# Generated by FakeRAM 2.0
VERSION 5.7 ;
BUSBITCHARS "[]" ;
PROPERTYDEFINITIONS
  MACRO width INTEGER ;
  MACRO depth INTEGER ;
  MACRO banks INTEGER ;
END PROPERTYDEFINITIONS
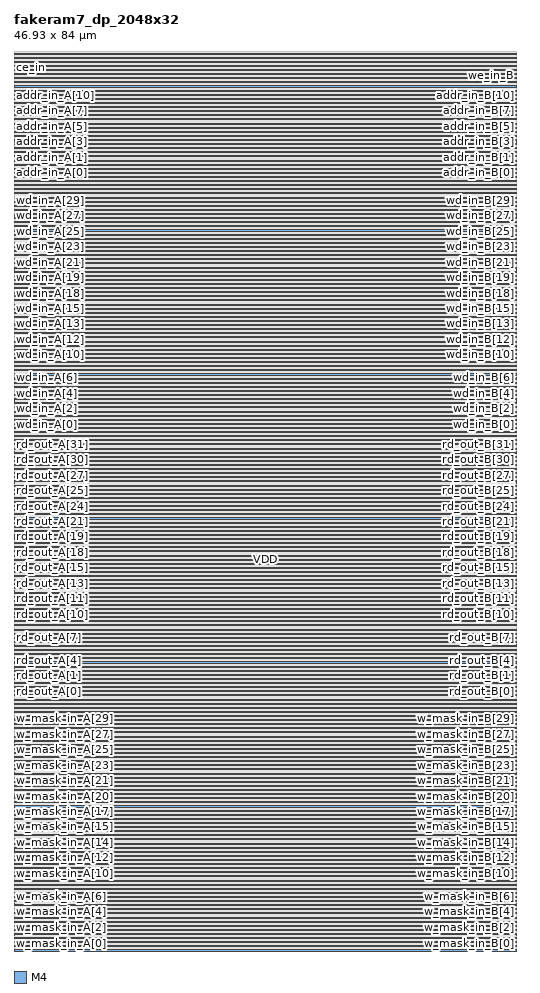
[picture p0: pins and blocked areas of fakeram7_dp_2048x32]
MACRO fakeram7_dp_2048x32
  PROPERTY width 32 ;
  PROPERTY depth 2048 ;
  PROPERTY banks 8 ;
  FOREIGN fakeram7_dp_2048x32 0 0 ;
  SYMMETRY X Y ;
  SIZE 46.930 BY 84.000 ;
  CLASS BLOCK ;
  PIN w_mask_in_A[0]
    DIRECTION INPUT ;
    USE SIGNAL ;
    SHAPE ABUTMENT ;
    PORT
      LAYER M4 ;
      RECT 0.000 0.048 0.024 0.072 ;
    END
  END w_mask_in_A[0]
  PIN w_mask_in_B[0]
    DIRECTION INPUT ;
    USE SIGNAL ;
    SHAPE ABUTMENT ;
    PORT
      LAYER M4 ;
      RECT 46.906 0.048 46.930 0.072 ;
    END
  END w_mask_in_B[0]
  PIN w_mask_in_A[1]
    DIRECTION INPUT ;
    USE SIGNAL ;
    SHAPE ABUTMENT ;
    PORT
      LAYER M4 ;
      RECT 0.000 0.768 0.024 0.792 ;
    END
  END w_mask_in_A[1]
  PIN w_mask_in_B[1]
    DIRECTION INPUT ;
    USE SIGNAL ;
    SHAPE ABUTMENT ;
    PORT
      LAYER M4 ;
      RECT 46.906 0.768 46.930 0.792 ;
    END
  END w_mask_in_B[1]
  PIN w_mask_in_A[2]
    DIRECTION INPUT ;
    USE SIGNAL ;
    SHAPE ABUTMENT ;
    PORT
      LAYER M4 ;
      RECT 0.000 1.488 0.024 1.512 ;
    END
  END w_mask_in_A[2]
  PIN w_mask_in_B[2]
    DIRECTION INPUT ;
    USE SIGNAL ;
    SHAPE ABUTMENT ;
    PORT
      LAYER M4 ;
      RECT 46.906 1.488 46.930 1.512 ;
    END
  END w_mask_in_B[2]
  PIN w_mask_in_A[3]
    DIRECTION INPUT ;
    USE SIGNAL ;
    SHAPE ABUTMENT ;
    PORT
      LAYER M4 ;
      RECT 0.000 2.208 0.024 2.232 ;
    END
  END w_mask_in_A[3]
  PIN w_mask_in_B[3]
    DIRECTION INPUT ;
    USE SIGNAL ;
    SHAPE ABUTMENT ;
    PORT
      LAYER M4 ;
      RECT 46.906 2.208 46.930 2.232 ;
    END
  END w_mask_in_B[3]
  PIN w_mask_in_A[4]
    DIRECTION INPUT ;
    USE SIGNAL ;
    SHAPE ABUTMENT ;
    PORT
      LAYER M4 ;
      RECT 0.000 2.928 0.024 2.952 ;
    END
  END w_mask_in_A[4]
  PIN w_mask_in_B[4]
    DIRECTION INPUT ;
    USE SIGNAL ;
    SHAPE ABUTMENT ;
    PORT
      LAYER M4 ;
      RECT 46.906 2.928 46.930 2.952 ;
    END
  END w_mask_in_B[4]
  PIN w_mask_in_A[5]
    DIRECTION INPUT ;
    USE SIGNAL ;
    SHAPE ABUTMENT ;
    PORT
      LAYER M4 ;
      RECT 0.000 3.648 0.024 3.672 ;
    END
  END w_mask_in_A[5]
  PIN w_mask_in_B[5]
    DIRECTION INPUT ;
    USE SIGNAL ;
    SHAPE ABUTMENT ;
    PORT
      LAYER M4 ;
      RECT 46.906 3.648 46.930 3.672 ;
    END
  END w_mask_in_B[5]
  PIN w_mask_in_A[6]
    DIRECTION INPUT ;
    USE SIGNAL ;
    SHAPE ABUTMENT ;
    PORT
      LAYER M4 ;
      RECT 0.000 4.368 0.024 4.392 ;
    END
  END w_mask_in_A[6]
  PIN w_mask_in_B[6]
    DIRECTION INPUT ;
    USE SIGNAL ;
    SHAPE ABUTMENT ;
    PORT
      LAYER M4 ;
      RECT 46.906 4.368 46.930 4.392 ;
    END
  END w_mask_in_B[6]
  PIN w_mask_in_A[7]
    DIRECTION INPUT ;
    USE SIGNAL ;
    SHAPE ABUTMENT ;
    PORT
      LAYER M4 ;
      RECT 0.000 5.088 0.024 5.112 ;
    END
  END w_mask_in_A[7]
  PIN w_mask_in_B[7]
    DIRECTION INPUT ;
    USE SIGNAL ;
    SHAPE ABUTMENT ;
    PORT
      LAYER M4 ;
      RECT 46.906 5.088 46.930 5.112 ;
    END
  END w_mask_in_B[7]
  PIN w_mask_in_A[8]
    DIRECTION INPUT ;
    USE SIGNAL ;
    SHAPE ABUTMENT ;
    PORT
      LAYER M4 ;
      RECT 0.000 5.808 0.024 5.832 ;
    END
  END w_mask_in_A[8]
  PIN w_mask_in_B[8]
    DIRECTION INPUT ;
    USE SIGNAL ;
    SHAPE ABUTMENT ;
    PORT
      LAYER M4 ;
      RECT 46.906 5.808 46.930 5.832 ;
    END
  END w_mask_in_B[8]
  PIN w_mask_in_A[9]
    DIRECTION INPUT ;
    USE SIGNAL ;
    SHAPE ABUTMENT ;
    PORT
      LAYER M4 ;
      RECT 0.000 6.528 0.024 6.552 ;
    END
  END w_mask_in_A[9]
  PIN w_mask_in_B[9]
    DIRECTION INPUT ;
    USE SIGNAL ;
    SHAPE ABUTMENT ;
    PORT
      LAYER M4 ;
      RECT 46.906 6.528 46.930 6.552 ;
    END
  END w_mask_in_B[9]
  PIN w_mask_in_A[10]
    DIRECTION INPUT ;
    USE SIGNAL ;
    SHAPE ABUTMENT ;
    PORT
      LAYER M4 ;
      RECT 0.000 7.248 0.024 7.272 ;
    END
  END w_mask_in_A[10]
  PIN w_mask_in_B[10]
    DIRECTION INPUT ;
    USE SIGNAL ;
    SHAPE ABUTMENT ;
    PORT
      LAYER M4 ;
      RECT 46.906 7.248 46.930 7.272 ;
    END
  END w_mask_in_B[10]
  PIN w_mask_in_A[11]
    DIRECTION INPUT ;
    USE SIGNAL ;
    SHAPE ABUTMENT ;
    PORT
      LAYER M4 ;
      RECT 0.000 7.968 0.024 7.992 ;
    END
  END w_mask_in_A[11]
  PIN w_mask_in_B[11]
    DIRECTION INPUT ;
    USE SIGNAL ;
    SHAPE ABUTMENT ;
    PORT
      LAYER M4 ;
      RECT 46.906 7.968 46.930 7.992 ;
    END
  END w_mask_in_B[11]
  PIN w_mask_in_A[12]
    DIRECTION INPUT ;
    USE SIGNAL ;
    SHAPE ABUTMENT ;
    PORT
      LAYER M4 ;
      RECT 0.000 8.688 0.024 8.712 ;
    END
  END w_mask_in_A[12]
  PIN w_mask_in_B[12]
    DIRECTION INPUT ;
    USE SIGNAL ;
    SHAPE ABUTMENT ;
    PORT
      LAYER M4 ;
      RECT 46.906 8.688 46.930 8.712 ;
    END
  END w_mask_in_B[12]
  PIN w_mask_in_A[13]
    DIRECTION INPUT ;
    USE SIGNAL ;
    SHAPE ABUTMENT ;
    PORT
      LAYER M4 ;
      RECT 0.000 9.408 0.024 9.432 ;
    END
  END w_mask_in_A[13]
  PIN w_mask_in_B[13]
    DIRECTION INPUT ;
    USE SIGNAL ;
    SHAPE ABUTMENT ;
    PORT
      LAYER M4 ;
      RECT 46.906 9.408 46.930 9.432 ;
    END
  END w_mask_in_B[13]
  PIN w_mask_in_A[14]
    DIRECTION INPUT ;
    USE SIGNAL ;
    SHAPE ABUTMENT ;
    PORT
      LAYER M4 ;
      RECT 0.000 10.128 0.024 10.152 ;
    END
  END w_mask_in_A[14]
  PIN w_mask_in_B[14]
    DIRECTION INPUT ;
    USE SIGNAL ;
    SHAPE ABUTMENT ;
    PORT
      LAYER M4 ;
      RECT 46.906 10.128 46.930 10.152 ;
    END
  END w_mask_in_B[14]
  PIN w_mask_in_A[15]
    DIRECTION INPUT ;
    USE SIGNAL ;
    SHAPE ABUTMENT ;
    PORT
      LAYER M4 ;
      RECT 0.000 10.848 0.024 10.872 ;
    END
  END w_mask_in_A[15]
  PIN w_mask_in_B[15]
    DIRECTION INPUT ;
    USE SIGNAL ;
    SHAPE ABUTMENT ;
    PORT
      LAYER M4 ;
      RECT 46.906 10.848 46.930 10.872 ;
    END
  END w_mask_in_B[15]
  PIN w_mask_in_A[16]
    DIRECTION INPUT ;
    USE SIGNAL ;
    SHAPE ABUTMENT ;
    PORT
      LAYER M4 ;
      RECT 0.000 11.568 0.024 11.592 ;
    END
  END w_mask_in_A[16]
  PIN w_mask_in_B[16]
    DIRECTION INPUT ;
    USE SIGNAL ;
    SHAPE ABUTMENT ;
    PORT
      LAYER M4 ;
      RECT 46.906 11.568 46.930 11.592 ;
    END
  END w_mask_in_B[16]
  PIN w_mask_in_A[17]
    DIRECTION INPUT ;
    USE SIGNAL ;
    SHAPE ABUTMENT ;
    PORT
      LAYER M4 ;
      RECT 0.000 12.288 0.024 12.312 ;
    END
  END w_mask_in_A[17]
  PIN w_mask_in_B[17]
    DIRECTION INPUT ;
    USE SIGNAL ;
    SHAPE ABUTMENT ;
    PORT
      LAYER M4 ;
      RECT 46.906 12.288 46.930 12.312 ;
    END
  END w_mask_in_B[17]
  PIN w_mask_in_A[18]
    DIRECTION INPUT ;
    USE SIGNAL ;
    SHAPE ABUTMENT ;
    PORT
      LAYER M4 ;
      RECT 0.000 13.008 0.024 13.032 ;
    END
  END w_mask_in_A[18]
  PIN w_mask_in_B[18]
    DIRECTION INPUT ;
    USE SIGNAL ;
    SHAPE ABUTMENT ;
    PORT
      LAYER M4 ;
      RECT 46.906 13.008 46.930 13.032 ;
    END
  END w_mask_in_B[18]
  PIN w_mask_in_A[19]
    DIRECTION INPUT ;
    USE SIGNAL ;
    SHAPE ABUTMENT ;
    PORT
      LAYER M4 ;
      RECT 0.000 13.728 0.024 13.752 ;
    END
  END w_mask_in_A[19]
  PIN w_mask_in_B[19]
    DIRECTION INPUT ;
    USE SIGNAL ;
    SHAPE ABUTMENT ;
    PORT
      LAYER M4 ;
      RECT 46.906 13.728 46.930 13.752 ;
    END
  END w_mask_in_B[19]
  PIN w_mask_in_A[20]
    DIRECTION INPUT ;
    USE SIGNAL ;
    SHAPE ABUTMENT ;
    PORT
      LAYER M4 ;
      RECT 0.000 14.448 0.024 14.472 ;
    END
  END w_mask_in_A[20]
  PIN w_mask_in_B[20]
    DIRECTION INPUT ;
    USE SIGNAL ;
    SHAPE ABUTMENT ;
    PORT
      LAYER M4 ;
      RECT 46.906 14.448 46.930 14.472 ;
    END
  END w_mask_in_B[20]
  PIN w_mask_in_A[21]
    DIRECTION INPUT ;
    USE SIGNAL ;
    SHAPE ABUTMENT ;
    PORT
      LAYER M4 ;
      RECT 0.000 15.168 0.024 15.192 ;
    END
  END w_mask_in_A[21]
  PIN w_mask_in_B[21]
    DIRECTION INPUT ;
    USE SIGNAL ;
    SHAPE ABUTMENT ;
    PORT
      LAYER M4 ;
      RECT 46.906 15.168 46.930 15.192 ;
    END
  END w_mask_in_B[21]
  PIN w_mask_in_A[22]
    DIRECTION INPUT ;
    USE SIGNAL ;
    SHAPE ABUTMENT ;
    PORT
      LAYER M4 ;
      RECT 0.000 15.888 0.024 15.912 ;
    END
  END w_mask_in_A[22]
  PIN w_mask_in_B[22]
    DIRECTION INPUT ;
    USE SIGNAL ;
    SHAPE ABUTMENT ;
    PORT
      LAYER M4 ;
      RECT 46.906 15.888 46.930 15.912 ;
    END
  END w_mask_in_B[22]
  PIN w_mask_in_A[23]
    DIRECTION INPUT ;
    USE SIGNAL ;
    SHAPE ABUTMENT ;
    PORT
      LAYER M4 ;
      RECT 0.000 16.608 0.024 16.632 ;
    END
  END w_mask_in_A[23]
  PIN w_mask_in_B[23]
    DIRECTION INPUT ;
    USE SIGNAL ;
    SHAPE ABUTMENT ;
    PORT
      LAYER M4 ;
      RECT 46.906 16.608 46.930 16.632 ;
    END
  END w_mask_in_B[23]
  PIN w_mask_in_A[24]
    DIRECTION INPUT ;
    USE SIGNAL ;
    SHAPE ABUTMENT ;
    PORT
      LAYER M4 ;
      RECT 0.000 17.328 0.024 17.352 ;
    END
  END w_mask_in_A[24]
  PIN w_mask_in_B[24]
    DIRECTION INPUT ;
    USE SIGNAL ;
    SHAPE ABUTMENT ;
    PORT
      LAYER M4 ;
      RECT 46.906 17.328 46.930 17.352 ;
    END
  END w_mask_in_B[24]
  PIN w_mask_in_A[25]
    DIRECTION INPUT ;
    USE SIGNAL ;
    SHAPE ABUTMENT ;
    PORT
      LAYER M4 ;
      RECT 0.000 18.048 0.024 18.072 ;
    END
  END w_mask_in_A[25]
  PIN w_mask_in_B[25]
    DIRECTION INPUT ;
    USE SIGNAL ;
    SHAPE ABUTMENT ;
    PORT
      LAYER M4 ;
      RECT 46.906 18.048 46.930 18.072 ;
    END
  END w_mask_in_B[25]
  PIN w_mask_in_A[26]
    DIRECTION INPUT ;
    USE SIGNAL ;
    SHAPE ABUTMENT ;
    PORT
      LAYER M4 ;
      RECT 0.000 18.768 0.024 18.792 ;
    END
  END w_mask_in_A[26]
  PIN w_mask_in_B[26]
    DIRECTION INPUT ;
    USE SIGNAL ;
    SHAPE ABUTMENT ;
    PORT
      LAYER M4 ;
      RECT 46.906 18.768 46.930 18.792 ;
    END
  END w_mask_in_B[26]
  PIN w_mask_in_A[27]
    DIRECTION INPUT ;
    USE SIGNAL ;
    SHAPE ABUTMENT ;
    PORT
      LAYER M4 ;
      RECT 0.000 19.488 0.024 19.512 ;
    END
  END w_mask_in_A[27]
  PIN w_mask_in_B[27]
    DIRECTION INPUT ;
    USE SIGNAL ;
    SHAPE ABUTMENT ;
    PORT
      LAYER M4 ;
      RECT 46.906 19.488 46.930 19.512 ;
    END
  END w_mask_in_B[27]
  PIN w_mask_in_A[28]
    DIRECTION INPUT ;
    USE SIGNAL ;
    SHAPE ABUTMENT ;
    PORT
      LAYER M4 ;
      RECT 0.000 20.208 0.024 20.232 ;
    END
  END w_mask_in_A[28]
  PIN w_mask_in_B[28]
    DIRECTION INPUT ;
    USE SIGNAL ;
    SHAPE ABUTMENT ;
    PORT
      LAYER M4 ;
      RECT 46.906 20.208 46.930 20.232 ;
    END
  END w_mask_in_B[28]
  PIN w_mask_in_A[29]
    DIRECTION INPUT ;
    USE SIGNAL ;
    SHAPE ABUTMENT ;
    PORT
      LAYER M4 ;
      RECT 0.000 20.928 0.024 20.952 ;
    END
  END w_mask_in_A[29]
  PIN w_mask_in_B[29]
    DIRECTION INPUT ;
    USE SIGNAL ;
    SHAPE ABUTMENT ;
    PORT
      LAYER M4 ;
      RECT 46.906 20.928 46.930 20.952 ;
    END
  END w_mask_in_B[29]
  PIN w_mask_in_A[30]
    DIRECTION INPUT ;
    USE SIGNAL ;
    SHAPE ABUTMENT ;
    PORT
      LAYER M4 ;
      RECT 0.000 21.648 0.024 21.672 ;
    END
  END w_mask_in_A[30]
  PIN w_mask_in_B[30]
    DIRECTION INPUT ;
    USE SIGNAL ;
    SHAPE ABUTMENT ;
    PORT
      LAYER M4 ;
      RECT 46.906 21.648 46.930 21.672 ;
    END
  END w_mask_in_B[30]
  PIN w_mask_in_A[31]
    DIRECTION INPUT ;
    USE SIGNAL ;
    SHAPE ABUTMENT ;
    PORT
      LAYER M4 ;
      RECT 0.000 22.368 0.024 22.392 ;
    END
  END w_mask_in_A[31]
  PIN w_mask_in_B[31]
    DIRECTION INPUT ;
    USE SIGNAL ;
    SHAPE ABUTMENT ;
    PORT
      LAYER M4 ;
      RECT 46.906 22.368 46.930 22.392 ;
    END
  END w_mask_in_B[31]
  PIN rd_out_A[0]
    DIRECTION OUTPUT ;
    USE SIGNAL ;
    SHAPE ABUTMENT ;
    PORT
      LAYER M4 ;
      RECT 0.000 24.240 0.024 24.264 ;
    END
  END rd_out_A[0]
  PIN rd_out_B[0]
    DIRECTION OUTPUT ;
    USE SIGNAL ;
    SHAPE ABUTMENT ;
    PORT
      LAYER M4 ;
      RECT 46.906 24.240 46.930 24.264 ;
    END
  END rd_out_B[0]
  PIN rd_out_A[1]
    DIRECTION OUTPUT ;
    USE SIGNAL ;
    SHAPE ABUTMENT ;
    PORT
      LAYER M4 ;
      RECT 0.000 24.960 0.024 24.984 ;
    END
  END rd_out_A[1]
  PIN rd_out_B[1]
    DIRECTION OUTPUT ;
    USE SIGNAL ;
    SHAPE ABUTMENT ;
    PORT
      LAYER M4 ;
      RECT 46.906 24.960 46.930 24.984 ;
    END
  END rd_out_B[1]
  PIN rd_out_A[2]
    DIRECTION OUTPUT ;
    USE SIGNAL ;
    SHAPE ABUTMENT ;
    PORT
      LAYER M4 ;
      RECT 0.000 25.680 0.024 25.704 ;
    END
  END rd_out_A[2]
  PIN rd_out_B[2]
    DIRECTION OUTPUT ;
    USE SIGNAL ;
    SHAPE ABUTMENT ;
    PORT
      LAYER M4 ;
      RECT 46.906 25.680 46.930 25.704 ;
    END
  END rd_out_B[2]
  PIN rd_out_A[3]
    DIRECTION OUTPUT ;
    USE SIGNAL ;
    SHAPE ABUTMENT ;
    PORT
      LAYER M4 ;
      RECT 0.000 26.400 0.024 26.424 ;
    END
  END rd_out_A[3]
  PIN rd_out_B[3]
    DIRECTION OUTPUT ;
    USE SIGNAL ;
    SHAPE ABUTMENT ;
    PORT
      LAYER M4 ;
      RECT 46.906 26.400 46.930 26.424 ;
    END
  END rd_out_B[3]
  PIN rd_out_A[4]
    DIRECTION OUTPUT ;
    USE SIGNAL ;
    SHAPE ABUTMENT ;
    PORT
      LAYER M4 ;
      RECT 0.000 27.120 0.024 27.144 ;
    END
  END rd_out_A[4]
  PIN rd_out_B[4]
    DIRECTION OUTPUT ;
    USE SIGNAL ;
    SHAPE ABUTMENT ;
    PORT
      LAYER M4 ;
      RECT 46.906 27.120 46.930 27.144 ;
    END
  END rd_out_B[4]
  PIN rd_out_A[5]
    DIRECTION OUTPUT ;
    USE SIGNAL ;
    SHAPE ABUTMENT ;
    PORT
      LAYER M4 ;
      RECT 0.000 27.840 0.024 27.864 ;
    END
  END rd_out_A[5]
  PIN rd_out_B[5]
    DIRECTION OUTPUT ;
    USE SIGNAL ;
    SHAPE ABUTMENT ;
    PORT
      LAYER M4 ;
      RECT 46.906 27.840 46.930 27.864 ;
    END
  END rd_out_B[5]
  PIN rd_out_A[6]
    DIRECTION OUTPUT ;
    USE SIGNAL ;
    SHAPE ABUTMENT ;
    PORT
      LAYER M4 ;
      RECT 0.000 28.560 0.024 28.584 ;
    END
  END rd_out_A[6]
  PIN rd_out_B[6]
    DIRECTION OUTPUT ;
    USE SIGNAL ;
    SHAPE ABUTMENT ;
    PORT
      LAYER M4 ;
      RECT 46.906 28.560 46.930 28.584 ;
    END
  END rd_out_B[6]
  PIN rd_out_A[7]
    DIRECTION OUTPUT ;
    USE SIGNAL ;
    SHAPE ABUTMENT ;
    PORT
      LAYER M4 ;
      RECT 0.000 29.280 0.024 29.304 ;
    END
  END rd_out_A[7]
  PIN rd_out_B[7]
    DIRECTION OUTPUT ;
    USE SIGNAL ;
    SHAPE ABUTMENT ;
    PORT
      LAYER M4 ;
      RECT 46.906 29.280 46.930 29.304 ;
    END
  END rd_out_B[7]
  PIN rd_out_A[8]
    DIRECTION OUTPUT ;
    USE SIGNAL ;
    SHAPE ABUTMENT ;
    PORT
      LAYER M4 ;
      RECT 0.000 30.000 0.024 30.024 ;
    END
  END rd_out_A[8]
  PIN rd_out_B[8]
    DIRECTION OUTPUT ;
    USE SIGNAL ;
    SHAPE ABUTMENT ;
    PORT
      LAYER M4 ;
      RECT 46.906 30.000 46.930 30.024 ;
    END
  END rd_out_B[8]
  PIN rd_out_A[9]
    DIRECTION OUTPUT ;
    USE SIGNAL ;
    SHAPE ABUTMENT ;
    PORT
      LAYER M4 ;
      RECT 0.000 30.720 0.024 30.744 ;
    END
  END rd_out_A[9]
  PIN rd_out_B[9]
    DIRECTION OUTPUT ;
    USE SIGNAL ;
    SHAPE ABUTMENT ;
    PORT
      LAYER M4 ;
      RECT 46.906 30.720 46.930 30.744 ;
    END
  END rd_out_B[9]
  PIN rd_out_A[10]
    DIRECTION OUTPUT ;
    USE SIGNAL ;
    SHAPE ABUTMENT ;
    PORT
      LAYER M4 ;
      RECT 0.000 31.440 0.024 31.464 ;
    END
  END rd_out_A[10]
  PIN rd_out_B[10]
    DIRECTION OUTPUT ;
    USE SIGNAL ;
    SHAPE ABUTMENT ;
    PORT
      LAYER M4 ;
      RECT 46.906 31.440 46.930 31.464 ;
    END
  END rd_out_B[10]
  PIN rd_out_A[11]
    DIRECTION OUTPUT ;
    USE SIGNAL ;
    SHAPE ABUTMENT ;
    PORT
      LAYER M4 ;
      RECT 0.000 32.160 0.024 32.184 ;
    END
  END rd_out_A[11]
  PIN rd_out_B[11]
    DIRECTION OUTPUT ;
    USE SIGNAL ;
    SHAPE ABUTMENT ;
    PORT
      LAYER M4 ;
      RECT 46.906 32.160 46.930 32.184 ;
    END
  END rd_out_B[11]
  PIN rd_out_A[12]
    DIRECTION OUTPUT ;
    USE SIGNAL ;
    SHAPE ABUTMENT ;
    PORT
      LAYER M4 ;
      RECT 0.000 32.880 0.024 32.904 ;
    END
  END rd_out_A[12]
  PIN rd_out_B[12]
    DIRECTION OUTPUT ;
    USE SIGNAL ;
    SHAPE ABUTMENT ;
    PORT
      LAYER M4 ;
      RECT 46.906 32.880 46.930 32.904 ;
    END
  END rd_out_B[12]
  PIN rd_out_A[13]
    DIRECTION OUTPUT ;
    USE SIGNAL ;
    SHAPE ABUTMENT ;
    PORT
      LAYER M4 ;
      RECT 0.000 33.600 0.024 33.624 ;
    END
  END rd_out_A[13]
  PIN rd_out_B[13]
    DIRECTION OUTPUT ;
    USE SIGNAL ;
    SHAPE ABUTMENT ;
    PORT
      LAYER M4 ;
      RECT 46.906 33.600 46.930 33.624 ;
    END
  END rd_out_B[13]
  PIN rd_out_A[14]
    DIRECTION OUTPUT ;
    USE SIGNAL ;
    SHAPE ABUTMENT ;
    PORT
      LAYER M4 ;
      RECT 0.000 34.320 0.024 34.344 ;
    END
  END rd_out_A[14]
  PIN rd_out_B[14]
    DIRECTION OUTPUT ;
    USE SIGNAL ;
    SHAPE ABUTMENT ;
    PORT
      LAYER M4 ;
      RECT 46.906 34.320 46.930 34.344 ;
    END
  END rd_out_B[14]
  PIN rd_out_A[15]
    DIRECTION OUTPUT ;
    USE SIGNAL ;
    SHAPE ABUTMENT ;
    PORT
      LAYER M4 ;
      RECT 0.000 35.040 0.024 35.064 ;
    END
  END rd_out_A[15]
  PIN rd_out_B[15]
    DIRECTION OUTPUT ;
    USE SIGNAL ;
    SHAPE ABUTMENT ;
    PORT
      LAYER M4 ;
      RECT 46.906 35.040 46.930 35.064 ;
    END
  END rd_out_B[15]
  PIN rd_out_A[16]
    DIRECTION OUTPUT ;
    USE SIGNAL ;
    SHAPE ABUTMENT ;
    PORT
      LAYER M4 ;
      RECT 0.000 35.760 0.024 35.784 ;
    END
  END rd_out_A[16]
  PIN rd_out_B[16]
    DIRECTION OUTPUT ;
    USE SIGNAL ;
    SHAPE ABUTMENT ;
    PORT
      LAYER M4 ;
      RECT 46.906 35.760 46.930 35.784 ;
    END
  END rd_out_B[16]
  PIN rd_out_A[17]
    DIRECTION OUTPUT ;
    USE SIGNAL ;
    SHAPE ABUTMENT ;
    PORT
      LAYER M4 ;
      RECT 0.000 36.480 0.024 36.504 ;
    END
  END rd_out_A[17]
  PIN rd_out_B[17]
    DIRECTION OUTPUT ;
    USE SIGNAL ;
    SHAPE ABUTMENT ;
    PORT
      LAYER M4 ;
      RECT 46.906 36.480 46.930 36.504 ;
    END
  END rd_out_B[17]
  PIN rd_out_A[18]
    DIRECTION OUTPUT ;
    USE SIGNAL ;
    SHAPE ABUTMENT ;
    PORT
      LAYER M4 ;
      RECT 0.000 37.200 0.024 37.224 ;
    END
  END rd_out_A[18]
  PIN rd_out_B[18]
    DIRECTION OUTPUT ;
    USE SIGNAL ;
    SHAPE ABUTMENT ;
    PORT
      LAYER M4 ;
      RECT 46.906 37.200 46.930 37.224 ;
    END
  END rd_out_B[18]
  PIN rd_out_A[19]
    DIRECTION OUTPUT ;
    USE SIGNAL ;
    SHAPE ABUTMENT ;
    PORT
      LAYER M4 ;
      RECT 0.000 37.920 0.024 37.944 ;
    END
  END rd_out_A[19]
  PIN rd_out_B[19]
    DIRECTION OUTPUT ;
    USE SIGNAL ;
    SHAPE ABUTMENT ;
    PORT
      LAYER M4 ;
      RECT 46.906 37.920 46.930 37.944 ;
    END
  END rd_out_B[19]
  PIN rd_out_A[20]
    DIRECTION OUTPUT ;
    USE SIGNAL ;
    SHAPE ABUTMENT ;
    PORT
      LAYER M4 ;
      RECT 0.000 38.640 0.024 38.664 ;
    END
  END rd_out_A[20]
  PIN rd_out_B[20]
    DIRECTION OUTPUT ;
    USE SIGNAL ;
    SHAPE ABUTMENT ;
    PORT
      LAYER M4 ;
      RECT 46.906 38.640 46.930 38.664 ;
    END
  END rd_out_B[20]
  PIN rd_out_A[21]
    DIRECTION OUTPUT ;
    USE SIGNAL ;
    SHAPE ABUTMENT ;
    PORT
      LAYER M4 ;
      RECT 0.000 39.360 0.024 39.384 ;
    END
  END rd_out_A[21]
  PIN rd_out_B[21]
    DIRECTION OUTPUT ;
    USE SIGNAL ;
    SHAPE ABUTMENT ;
    PORT
      LAYER M4 ;
      RECT 46.906 39.360 46.930 39.384 ;
    END
  END rd_out_B[21]
  PIN rd_out_A[22]
    DIRECTION OUTPUT ;
    USE SIGNAL ;
    SHAPE ABUTMENT ;
    PORT
      LAYER M4 ;
      RECT 0.000 40.080 0.024 40.104 ;
    END
  END rd_out_A[22]
  PIN rd_out_B[22]
    DIRECTION OUTPUT ;
    USE SIGNAL ;
    SHAPE ABUTMENT ;
    PORT
      LAYER M4 ;
      RECT 46.906 40.080 46.930 40.104 ;
    END
  END rd_out_B[22]
  PIN rd_out_A[23]
    DIRECTION OUTPUT ;
    USE SIGNAL ;
    SHAPE ABUTMENT ;
    PORT
      LAYER M4 ;
      RECT 0.000 40.800 0.024 40.824 ;
    END
  END rd_out_A[23]
  PIN rd_out_B[23]
    DIRECTION OUTPUT ;
    USE SIGNAL ;
    SHAPE ABUTMENT ;
    PORT
      LAYER M4 ;
      RECT 46.906 40.800 46.930 40.824 ;
    END
  END rd_out_B[23]
  PIN rd_out_A[24]
    DIRECTION OUTPUT ;
    USE SIGNAL ;
    SHAPE ABUTMENT ;
    PORT
      LAYER M4 ;
      RECT 0.000 41.520 0.024 41.544 ;
    END
  END rd_out_A[24]
  PIN rd_out_B[24]
    DIRECTION OUTPUT ;
    USE SIGNAL ;
    SHAPE ABUTMENT ;
    PORT
      LAYER M4 ;
      RECT 46.906 41.520 46.930 41.544 ;
    END
  END rd_out_B[24]
  PIN rd_out_A[25]
    DIRECTION OUTPUT ;
    USE SIGNAL ;
    SHAPE ABUTMENT ;
    PORT
      LAYER M4 ;
      RECT 0.000 42.240 0.024 42.264 ;
    END
  END rd_out_A[25]
  PIN rd_out_B[25]
    DIRECTION OUTPUT ;
    USE SIGNAL ;
    SHAPE ABUTMENT ;
    PORT
      LAYER M4 ;
      RECT 46.906 42.240 46.930 42.264 ;
    END
  END rd_out_B[25]
  PIN rd_out_A[26]
    DIRECTION OUTPUT ;
    USE SIGNAL ;
    SHAPE ABUTMENT ;
    PORT
      LAYER M4 ;
      RECT 0.000 42.960 0.024 42.984 ;
    END
  END rd_out_A[26]
  PIN rd_out_B[26]
    DIRECTION OUTPUT ;
    USE SIGNAL ;
    SHAPE ABUTMENT ;
    PORT
      LAYER M4 ;
      RECT 46.906 42.960 46.930 42.984 ;
    END
  END rd_out_B[26]
  PIN rd_out_A[27]
    DIRECTION OUTPUT ;
    USE SIGNAL ;
    SHAPE ABUTMENT ;
    PORT
      LAYER M4 ;
      RECT 0.000 43.680 0.024 43.704 ;
    END
  END rd_out_A[27]
  PIN rd_out_B[27]
    DIRECTION OUTPUT ;
    USE SIGNAL ;
    SHAPE ABUTMENT ;
    PORT
      LAYER M4 ;
      RECT 46.906 43.680 46.930 43.704 ;
    END
  END rd_out_B[27]
  PIN rd_out_A[28]
    DIRECTION OUTPUT ;
    USE SIGNAL ;
    SHAPE ABUTMENT ;
    PORT
      LAYER M4 ;
      RECT 0.000 44.400 0.024 44.424 ;
    END
  END rd_out_A[28]
  PIN rd_out_B[28]
    DIRECTION OUTPUT ;
    USE SIGNAL ;
    SHAPE ABUTMENT ;
    PORT
      LAYER M4 ;
      RECT 46.906 44.400 46.930 44.424 ;
    END
  END rd_out_B[28]
  PIN rd_out_A[29]
    DIRECTION OUTPUT ;
    USE SIGNAL ;
    SHAPE ABUTMENT ;
    PORT
      LAYER M4 ;
      RECT 0.000 45.120 0.024 45.144 ;
    END
  END rd_out_A[29]
  PIN rd_out_B[29]
    DIRECTION OUTPUT ;
    USE SIGNAL ;
    SHAPE ABUTMENT ;
    PORT
      LAYER M4 ;
      RECT 46.906 45.120 46.930 45.144 ;
    END
  END rd_out_B[29]
  PIN rd_out_A[30]
    DIRECTION OUTPUT ;
    USE SIGNAL ;
    SHAPE ABUTMENT ;
    PORT
      LAYER M4 ;
      RECT 0.000 45.840 0.024 45.864 ;
    END
  END rd_out_A[30]
  PIN rd_out_B[30]
    DIRECTION OUTPUT ;
    USE SIGNAL ;
    SHAPE ABUTMENT ;
    PORT
      LAYER M4 ;
      RECT 46.906 45.840 46.930 45.864 ;
    END
  END rd_out_B[30]
  PIN rd_out_A[31]
    DIRECTION OUTPUT ;
    USE SIGNAL ;
    SHAPE ABUTMENT ;
    PORT
      LAYER M4 ;
      RECT 0.000 46.560 0.024 46.584 ;
    END
  END rd_out_A[31]
  PIN rd_out_B[31]
    DIRECTION OUTPUT ;
    USE SIGNAL ;
    SHAPE ABUTMENT ;
    PORT
      LAYER M4 ;
      RECT 46.906 46.560 46.930 46.584 ;
    END
  END rd_out_B[31]
  PIN wd_in_A[0]
    DIRECTION INPUT ;
    USE SIGNAL ;
    SHAPE ABUTMENT ;
    PORT
      LAYER M4 ;
      RECT 0.000 48.432 0.024 48.456 ;
    END
  END wd_in_A[0]
  PIN wd_in_B[0]
    DIRECTION INPUT ;
    USE SIGNAL ;
    SHAPE ABUTMENT ;
    PORT
      LAYER M4 ;
      RECT 46.906 48.432 46.930 48.456 ;
    END
  END wd_in_B[0]
  PIN wd_in_A[1]
    DIRECTION INPUT ;
    USE SIGNAL ;
    SHAPE ABUTMENT ;
    PORT
      LAYER M4 ;
      RECT 0.000 49.152 0.024 49.176 ;
    END
  END wd_in_A[1]
  PIN wd_in_B[1]
    DIRECTION INPUT ;
    USE SIGNAL ;
    SHAPE ABUTMENT ;
    PORT
      LAYER M4 ;
      RECT 46.906 49.152 46.930 49.176 ;
    END
  END wd_in_B[1]
  PIN wd_in_A[2]
    DIRECTION INPUT ;
    USE SIGNAL ;
    SHAPE ABUTMENT ;
    PORT
      LAYER M4 ;
      RECT 0.000 49.872 0.024 49.896 ;
    END
  END wd_in_A[2]
  PIN wd_in_B[2]
    DIRECTION INPUT ;
    USE SIGNAL ;
    SHAPE ABUTMENT ;
    PORT
      LAYER M4 ;
      RECT 46.906 49.872 46.930 49.896 ;
    END
  END wd_in_B[2]
  PIN wd_in_A[3]
    DIRECTION INPUT ;
    USE SIGNAL ;
    SHAPE ABUTMENT ;
    PORT
      LAYER M4 ;
      RECT 0.000 50.592 0.024 50.616 ;
    END
  END wd_in_A[3]
  PIN wd_in_B[3]
    DIRECTION INPUT ;
    USE SIGNAL ;
    SHAPE ABUTMENT ;
    PORT
      LAYER M4 ;
      RECT 46.906 50.592 46.930 50.616 ;
    END
  END wd_in_B[3]
  PIN wd_in_A[4]
    DIRECTION INPUT ;
    USE SIGNAL ;
    SHAPE ABUTMENT ;
    PORT
      LAYER M4 ;
      RECT 0.000 51.312 0.024 51.336 ;
    END
  END wd_in_A[4]
  PIN wd_in_B[4]
    DIRECTION INPUT ;
    USE SIGNAL ;
    SHAPE ABUTMENT ;
    PORT
      LAYER M4 ;
      RECT 46.906 51.312 46.930 51.336 ;
    END
  END wd_in_B[4]
  PIN wd_in_A[5]
    DIRECTION INPUT ;
    USE SIGNAL ;
    SHAPE ABUTMENT ;
    PORT
      LAYER M4 ;
      RECT 0.000 52.032 0.024 52.056 ;
    END
  END wd_in_A[5]
  PIN wd_in_B[5]
    DIRECTION INPUT ;
    USE SIGNAL ;
    SHAPE ABUTMENT ;
    PORT
      LAYER M4 ;
      RECT 46.906 52.032 46.930 52.056 ;
    END
  END wd_in_B[5]
  PIN wd_in_A[6]
    DIRECTION INPUT ;
    USE SIGNAL ;
    SHAPE ABUTMENT ;
    PORT
      LAYER M4 ;
      RECT 0.000 52.752 0.024 52.776 ;
    END
  END wd_in_A[6]
  PIN wd_in_B[6]
    DIRECTION INPUT ;
    USE SIGNAL ;
    SHAPE ABUTMENT ;
    PORT
      LAYER M4 ;
      RECT 46.906 52.752 46.930 52.776 ;
    END
  END wd_in_B[6]
  PIN wd_in_A[7]
    DIRECTION INPUT ;
    USE SIGNAL ;
    SHAPE ABUTMENT ;
    PORT
      LAYER M4 ;
      RECT 0.000 53.472 0.024 53.496 ;
    END
  END wd_in_A[7]
  PIN wd_in_B[7]
    DIRECTION INPUT ;
    USE SIGNAL ;
    SHAPE ABUTMENT ;
    PORT
      LAYER M4 ;
      RECT 46.906 53.472 46.930 53.496 ;
    END
  END wd_in_B[7]
  PIN wd_in_A[8]
    DIRECTION INPUT ;
    USE SIGNAL ;
    SHAPE ABUTMENT ;
    PORT
      LAYER M4 ;
      RECT 0.000 54.192 0.024 54.216 ;
    END
  END wd_in_A[8]
  PIN wd_in_B[8]
    DIRECTION INPUT ;
    USE SIGNAL ;
    SHAPE ABUTMENT ;
    PORT
      LAYER M4 ;
      RECT 46.906 54.192 46.930 54.216 ;
    END
  END wd_in_B[8]
  PIN wd_in_A[9]
    DIRECTION INPUT ;
    USE SIGNAL ;
    SHAPE ABUTMENT ;
    PORT
      LAYER M4 ;
      RECT 0.000 54.912 0.024 54.936 ;
    END
  END wd_in_A[9]
  PIN wd_in_B[9]
    DIRECTION INPUT ;
    USE SIGNAL ;
    SHAPE ABUTMENT ;
    PORT
      LAYER M4 ;
      RECT 46.906 54.912 46.930 54.936 ;
    END
  END wd_in_B[9]
  PIN wd_in_A[10]
    DIRECTION INPUT ;
    USE SIGNAL ;
    SHAPE ABUTMENT ;
    PORT
      LAYER M4 ;
      RECT 0.000 55.632 0.024 55.656 ;
    END
  END wd_in_A[10]
  PIN wd_in_B[10]
    DIRECTION INPUT ;
    USE SIGNAL ;
    SHAPE ABUTMENT ;
    PORT
      LAYER M4 ;
      RECT 46.906 55.632 46.930 55.656 ;
    END
  END wd_in_B[10]
  PIN wd_in_A[11]
    DIRECTION INPUT ;
    USE SIGNAL ;
    SHAPE ABUTMENT ;
    PORT
      LAYER M4 ;
      RECT 0.000 56.352 0.024 56.376 ;
    END
  END wd_in_A[11]
  PIN wd_in_B[11]
    DIRECTION INPUT ;
    USE SIGNAL ;
    SHAPE ABUTMENT ;
    PORT
      LAYER M4 ;
      RECT 46.906 56.352 46.930 56.376 ;
    END
  END wd_in_B[11]
  PIN wd_in_A[12]
    DIRECTION INPUT ;
    USE SIGNAL ;
    SHAPE ABUTMENT ;
    PORT
      LAYER M4 ;
      RECT 0.000 57.072 0.024 57.096 ;
    END
  END wd_in_A[12]
  PIN wd_in_B[12]
    DIRECTION INPUT ;
    USE SIGNAL ;
    SHAPE ABUTMENT ;
    PORT
      LAYER M4 ;
      RECT 46.906 57.072 46.930 57.096 ;
    END
  END wd_in_B[12]
  PIN wd_in_A[13]
    DIRECTION INPUT ;
    USE SIGNAL ;
    SHAPE ABUTMENT ;
    PORT
      LAYER M4 ;
      RECT 0.000 57.792 0.024 57.816 ;
    END
  END wd_in_A[13]
  PIN wd_in_B[13]
    DIRECTION INPUT ;
    USE SIGNAL ;
    SHAPE ABUTMENT ;
    PORT
      LAYER M4 ;
      RECT 46.906 57.792 46.930 57.816 ;
    END
  END wd_in_B[13]
  PIN wd_in_A[14]
    DIRECTION INPUT ;
    USE SIGNAL ;
    SHAPE ABUTMENT ;
    PORT
      LAYER M4 ;
      RECT 0.000 58.512 0.024 58.536 ;
    END
  END wd_in_A[14]
  PIN wd_in_B[14]
    DIRECTION INPUT ;
    USE SIGNAL ;
    SHAPE ABUTMENT ;
    PORT
      LAYER M4 ;
      RECT 46.906 58.512 46.930 58.536 ;
    END
  END wd_in_B[14]
  PIN wd_in_A[15]
    DIRECTION INPUT ;
    USE SIGNAL ;
    SHAPE ABUTMENT ;
    PORT
      LAYER M4 ;
      RECT 0.000 59.232 0.024 59.256 ;
    END
  END wd_in_A[15]
  PIN wd_in_B[15]
    DIRECTION INPUT ;
    USE SIGNAL ;
    SHAPE ABUTMENT ;
    PORT
      LAYER M4 ;
      RECT 46.906 59.232 46.930 59.256 ;
    END
  END wd_in_B[15]
  PIN wd_in_A[16]
    DIRECTION INPUT ;
    USE SIGNAL ;
    SHAPE ABUTMENT ;
    PORT
      LAYER M4 ;
      RECT 0.000 59.952 0.024 59.976 ;
    END
  END wd_in_A[16]
  PIN wd_in_B[16]
    DIRECTION INPUT ;
    USE SIGNAL ;
    SHAPE ABUTMENT ;
    PORT
      LAYER M4 ;
      RECT 46.906 59.952 46.930 59.976 ;
    END
  END wd_in_B[16]
  PIN wd_in_A[17]
    DIRECTION INPUT ;
    USE SIGNAL ;
    SHAPE ABUTMENT ;
    PORT
      LAYER M4 ;
      RECT 0.000 60.672 0.024 60.696 ;
    END
  END wd_in_A[17]
  PIN wd_in_B[17]
    DIRECTION INPUT ;
    USE SIGNAL ;
    SHAPE ABUTMENT ;
    PORT
      LAYER M4 ;
      RECT 46.906 60.672 46.930 60.696 ;
    END
  END wd_in_B[17]
  PIN wd_in_A[18]
    DIRECTION INPUT ;
    USE SIGNAL ;
    SHAPE ABUTMENT ;
    PORT
      LAYER M4 ;
      RECT 0.000 61.392 0.024 61.416 ;
    END
  END wd_in_A[18]
  PIN wd_in_B[18]
    DIRECTION INPUT ;
    USE SIGNAL ;
    SHAPE ABUTMENT ;
    PORT
      LAYER M4 ;
      RECT 46.906 61.392 46.930 61.416 ;
    END
  END wd_in_B[18]
  PIN wd_in_A[19]
    DIRECTION INPUT ;
    USE SIGNAL ;
    SHAPE ABUTMENT ;
    PORT
      LAYER M4 ;
      RECT 0.000 62.112 0.024 62.136 ;
    END
  END wd_in_A[19]
  PIN wd_in_B[19]
    DIRECTION INPUT ;
    USE SIGNAL ;
    SHAPE ABUTMENT ;
    PORT
      LAYER M4 ;
      RECT 46.906 62.112 46.930 62.136 ;
    END
  END wd_in_B[19]
  PIN wd_in_A[20]
    DIRECTION INPUT ;
    USE SIGNAL ;
    SHAPE ABUTMENT ;
    PORT
      LAYER M4 ;
      RECT 0.000 62.832 0.024 62.856 ;
    END
  END wd_in_A[20]
  PIN wd_in_B[20]
    DIRECTION INPUT ;
    USE SIGNAL ;
    SHAPE ABUTMENT ;
    PORT
      LAYER M4 ;
      RECT 46.906 62.832 46.930 62.856 ;
    END
  END wd_in_B[20]
  PIN wd_in_A[21]
    DIRECTION INPUT ;
    USE SIGNAL ;
    SHAPE ABUTMENT ;
    PORT
      LAYER M4 ;
      RECT 0.000 63.552 0.024 63.576 ;
    END
  END wd_in_A[21]
  PIN wd_in_B[21]
    DIRECTION INPUT ;
    USE SIGNAL ;
    SHAPE ABUTMENT ;
    PORT
      LAYER M4 ;
      RECT 46.906 63.552 46.930 63.576 ;
    END
  END wd_in_B[21]
  PIN wd_in_A[22]
    DIRECTION INPUT ;
    USE SIGNAL ;
    SHAPE ABUTMENT ;
    PORT
      LAYER M4 ;
      RECT 0.000 64.272 0.024 64.296 ;
    END
  END wd_in_A[22]
  PIN wd_in_B[22]
    DIRECTION INPUT ;
    USE SIGNAL ;
    SHAPE ABUTMENT ;
    PORT
      LAYER M4 ;
      RECT 46.906 64.272 46.930 64.296 ;
    END
  END wd_in_B[22]
  PIN wd_in_A[23]
    DIRECTION INPUT ;
    USE SIGNAL ;
    SHAPE ABUTMENT ;
    PORT
      LAYER M4 ;
      RECT 0.000 64.992 0.024 65.016 ;
    END
  END wd_in_A[23]
  PIN wd_in_B[23]
    DIRECTION INPUT ;
    USE SIGNAL ;
    SHAPE ABUTMENT ;
    PORT
      LAYER M4 ;
      RECT 46.906 64.992 46.930 65.016 ;
    END
  END wd_in_B[23]
  PIN wd_in_A[24]
    DIRECTION INPUT ;
    USE SIGNAL ;
    SHAPE ABUTMENT ;
    PORT
      LAYER M4 ;
      RECT 0.000 65.712 0.024 65.736 ;
    END
  END wd_in_A[24]
  PIN wd_in_B[24]
    DIRECTION INPUT ;
    USE SIGNAL ;
    SHAPE ABUTMENT ;
    PORT
      LAYER M4 ;
      RECT 46.906 65.712 46.930 65.736 ;
    END
  END wd_in_B[24]
  PIN wd_in_A[25]
    DIRECTION INPUT ;
    USE SIGNAL ;
    SHAPE ABUTMENT ;
    PORT
      LAYER M4 ;
      RECT 0.000 66.432 0.024 66.456 ;
    END
  END wd_in_A[25]
  PIN wd_in_B[25]
    DIRECTION INPUT ;
    USE SIGNAL ;
    SHAPE ABUTMENT ;
    PORT
      LAYER M4 ;
      RECT 46.906 66.432 46.930 66.456 ;
    END
  END wd_in_B[25]
  PIN wd_in_A[26]
    DIRECTION INPUT ;
    USE SIGNAL ;
    SHAPE ABUTMENT ;
    PORT
      LAYER M4 ;
      RECT 0.000 67.152 0.024 67.176 ;
    END
  END wd_in_A[26]
  PIN wd_in_B[26]
    DIRECTION INPUT ;
    USE SIGNAL ;
    SHAPE ABUTMENT ;
    PORT
      LAYER M4 ;
      RECT 46.906 67.152 46.930 67.176 ;
    END
  END wd_in_B[26]
  PIN wd_in_A[27]
    DIRECTION INPUT ;
    USE SIGNAL ;
    SHAPE ABUTMENT ;
    PORT
      LAYER M4 ;
      RECT 0.000 67.872 0.024 67.896 ;
    END
  END wd_in_A[27]
  PIN wd_in_B[27]
    DIRECTION INPUT ;
    USE SIGNAL ;
    SHAPE ABUTMENT ;
    PORT
      LAYER M4 ;
      RECT 46.906 67.872 46.930 67.896 ;
    END
  END wd_in_B[27]
  PIN wd_in_A[28]
    DIRECTION INPUT ;
    USE SIGNAL ;
    SHAPE ABUTMENT ;
    PORT
      LAYER M4 ;
      RECT 0.000 68.592 0.024 68.616 ;
    END
  END wd_in_A[28]
  PIN wd_in_B[28]
    DIRECTION INPUT ;
    USE SIGNAL ;
    SHAPE ABUTMENT ;
    PORT
      LAYER M4 ;
      RECT 46.906 68.592 46.930 68.616 ;
    END
  END wd_in_B[28]
  PIN wd_in_A[29]
    DIRECTION INPUT ;
    USE SIGNAL ;
    SHAPE ABUTMENT ;
    PORT
      LAYER M4 ;
      RECT 0.000 69.312 0.024 69.336 ;
    END
  END wd_in_A[29]
  PIN wd_in_B[29]
    DIRECTION INPUT ;
    USE SIGNAL ;
    SHAPE ABUTMENT ;
    PORT
      LAYER M4 ;
      RECT 46.906 69.312 46.930 69.336 ;
    END
  END wd_in_B[29]
  PIN wd_in_A[30]
    DIRECTION INPUT ;
    USE SIGNAL ;
    SHAPE ABUTMENT ;
    PORT
      LAYER M4 ;
      RECT 0.000 70.032 0.024 70.056 ;
    END
  END wd_in_A[30]
  PIN wd_in_B[30]
    DIRECTION INPUT ;
    USE SIGNAL ;
    SHAPE ABUTMENT ;
    PORT
      LAYER M4 ;
      RECT 46.906 70.032 46.930 70.056 ;
    END
  END wd_in_B[30]
  PIN wd_in_A[31]
    DIRECTION INPUT ;
    USE SIGNAL ;
    SHAPE ABUTMENT ;
    PORT
      LAYER M4 ;
      RECT 0.000 70.752 0.024 70.776 ;
    END
  END wd_in_A[31]
  PIN wd_in_B[31]
    DIRECTION INPUT ;
    USE SIGNAL ;
    SHAPE ABUTMENT ;
    PORT
      LAYER M4 ;
      RECT 46.906 70.752 46.930 70.776 ;
    END
  END wd_in_B[31]
  PIN addr_in_A[0]
    DIRECTION INPUT ;
    USE SIGNAL ;
    SHAPE ABUTMENT ;
    PORT
      LAYER M4 ;
      RECT 0.000 72.624 0.024 72.648 ;
    END
  END addr_in_A[0]
  PIN addr_in_B[0]
    DIRECTION INPUT ;
    USE SIGNAL ;
    SHAPE ABUTMENT ;
    PORT
      LAYER M4 ;
      RECT 46.906 72.624 46.930 72.648 ;
    END
  END addr_in_B[0]
  PIN addr_in_A[1]
    DIRECTION INPUT ;
    USE SIGNAL ;
    SHAPE ABUTMENT ;
    PORT
      LAYER M4 ;
      RECT 0.000 73.344 0.024 73.368 ;
    END
  END addr_in_A[1]
  PIN addr_in_B[1]
    DIRECTION INPUT ;
    USE SIGNAL ;
    SHAPE ABUTMENT ;
    PORT
      LAYER M4 ;
      RECT 46.906 73.344 46.930 73.368 ;
    END
  END addr_in_B[1]
  PIN addr_in_A[2]
    DIRECTION INPUT ;
    USE SIGNAL ;
    SHAPE ABUTMENT ;
    PORT
      LAYER M4 ;
      RECT 0.000 74.064 0.024 74.088 ;
    END
  END addr_in_A[2]
  PIN addr_in_B[2]
    DIRECTION INPUT ;
    USE SIGNAL ;
    SHAPE ABUTMENT ;
    PORT
      LAYER M4 ;
      RECT 46.906 74.064 46.930 74.088 ;
    END
  END addr_in_B[2]
  PIN addr_in_A[3]
    DIRECTION INPUT ;
    USE SIGNAL ;
    SHAPE ABUTMENT ;
    PORT
      LAYER M4 ;
      RECT 0.000 74.784 0.024 74.808 ;
    END
  END addr_in_A[3]
  PIN addr_in_B[3]
    DIRECTION INPUT ;
    USE SIGNAL ;
    SHAPE ABUTMENT ;
    PORT
      LAYER M4 ;
      RECT 46.906 74.784 46.930 74.808 ;
    END
  END addr_in_B[3]
  PIN addr_in_A[4]
    DIRECTION INPUT ;
    USE SIGNAL ;
    SHAPE ABUTMENT ;
    PORT
      LAYER M4 ;
      RECT 0.000 75.504 0.024 75.528 ;
    END
  END addr_in_A[4]
  PIN addr_in_B[4]
    DIRECTION INPUT ;
    USE SIGNAL ;
    SHAPE ABUTMENT ;
    PORT
      LAYER M4 ;
      RECT 46.906 75.504 46.930 75.528 ;
    END
  END addr_in_B[4]
  PIN addr_in_A[5]
    DIRECTION INPUT ;
    USE SIGNAL ;
    SHAPE ABUTMENT ;
    PORT
      LAYER M4 ;
      RECT 0.000 76.224 0.024 76.248 ;
    END
  END addr_in_A[5]
  PIN addr_in_B[5]
    DIRECTION INPUT ;
    USE SIGNAL ;
    SHAPE ABUTMENT ;
    PORT
      LAYER M4 ;
      RECT 46.906 76.224 46.930 76.248 ;
    END
  END addr_in_B[5]
  PIN addr_in_A[6]
    DIRECTION INPUT ;
    USE SIGNAL ;
    SHAPE ABUTMENT ;
    PORT
      LAYER M4 ;
      RECT 0.000 76.944 0.024 76.968 ;
    END
  END addr_in_A[6]
  PIN addr_in_B[6]
    DIRECTION INPUT ;
    USE SIGNAL ;
    SHAPE ABUTMENT ;
    PORT
      LAYER M4 ;
      RECT 46.906 76.944 46.930 76.968 ;
    END
  END addr_in_B[6]
  PIN addr_in_A[7]
    DIRECTION INPUT ;
    USE SIGNAL ;
    SHAPE ABUTMENT ;
    PORT
      LAYER M4 ;
      RECT 0.000 77.664 0.024 77.688 ;
    END
  END addr_in_A[7]
  PIN addr_in_B[7]
    DIRECTION INPUT ;
    USE SIGNAL ;
    SHAPE ABUTMENT ;
    PORT
      LAYER M4 ;
      RECT 46.906 77.664 46.930 77.688 ;
    END
  END addr_in_B[7]
  PIN addr_in_A[8]
    DIRECTION INPUT ;
    USE SIGNAL ;
    SHAPE ABUTMENT ;
    PORT
      LAYER M4 ;
      RECT 0.000 78.384 0.024 78.408 ;
    END
  END addr_in_A[8]
  PIN addr_in_B[8]
    DIRECTION INPUT ;
    USE SIGNAL ;
    SHAPE ABUTMENT ;
    PORT
      LAYER M4 ;
      RECT 46.906 78.384 46.930 78.408 ;
    END
  END addr_in_B[8]
  PIN addr_in_A[9]
    DIRECTION INPUT ;
    USE SIGNAL ;
    SHAPE ABUTMENT ;
    PORT
      LAYER M4 ;
      RECT 0.000 79.104 0.024 79.128 ;
    END
  END addr_in_A[9]
  PIN addr_in_B[9]
    DIRECTION INPUT ;
    USE SIGNAL ;
    SHAPE ABUTMENT ;
    PORT
      LAYER M4 ;
      RECT 46.906 79.104 46.930 79.128 ;
    END
  END addr_in_B[9]
  PIN addr_in_A[10]
    DIRECTION INPUT ;
    USE SIGNAL ;
    SHAPE ABUTMENT ;
    PORT
      LAYER M4 ;
      RECT 0.000 79.824 0.024 79.848 ;
    END
  END addr_in_A[10]
  PIN addr_in_B[10]
    DIRECTION INPUT ;
    USE SIGNAL ;
    SHAPE ABUTMENT ;
    PORT
      LAYER M4 ;
      RECT 46.906 79.824 46.930 79.848 ;
    END
  END addr_in_B[10]
  PIN we_in_A
    DIRECTION INPUT ;
    USE SIGNAL ;
    SHAPE ABUTMENT ;
    PORT
      LAYER M4 ;
      RECT 0.000 81.696 0.024 81.720 ;
    END
  END we_in_A
  PIN we_in_B
    DIRECTION INPUT ;
    USE SIGNAL ;
    SHAPE ABUTMENT ;
    PORT
      LAYER M4 ;
      RECT 46.906 81.696 46.930 81.720 ;
    END
  END we_in_B
  PIN ce_in
    DIRECTION INPUT ;
    USE SIGNAL ;
    SHAPE ABUTMENT ;
    PORT
      LAYER M4 ;
      RECT 0.000 82.416 0.024 82.440 ;
    END
  END ce_in
  PIN clk
    DIRECTION INPUT ;
    USE SIGNAL ;
    SHAPE ABUTMENT ;
    PORT
      LAYER M4 ;
      RECT 0.000 83.136 0.024 83.160 ;
    END
  END clk
  PIN VSS
    DIRECTION INOUT ;
    USE GROUND ;
    PORT
      LAYER M4 ;
      RECT 0.048 0.000 46.882 0.096 ;
      RECT 0.048 0.768 46.882 0.864 ;
      RECT 0.048 1.536 46.882 1.632 ;
      RECT 0.048 2.304 46.882 2.400 ;
      RECT 0.048 3.072 46.882 3.168 ;
      RECT 0.048 3.840 46.882 3.936 ;
      RECT 0.048 4.608 46.882 4.704 ;
      RECT 0.048 5.376 46.882 5.472 ;
      RECT 0.048 6.144 46.882 6.240 ;
      RECT 0.048 6.912 46.882 7.008 ;
      RECT 0.048 7.680 46.882 7.776 ;
      RECT 0.048 8.448 46.882 8.544 ;
      RECT 0.048 9.216 46.882 9.312 ;
      RECT 0.048 9.984 46.882 10.080 ;
      RECT 0.048 10.752 46.882 10.848 ;
      RECT 0.048 11.520 46.882 11.616 ;
      RECT 0.048 12.288 46.882 12.384 ;
      RECT 0.048 13.056 46.882 13.152 ;
      RECT 0.048 13.824 46.882 13.920 ;
      RECT 0.048 14.592 46.882 14.688 ;
      RECT 0.048 15.360 46.882 15.456 ;
      RECT 0.048 16.128 46.882 16.224 ;
      RECT 0.048 16.896 46.882 16.992 ;
      RECT 0.048 17.664 46.882 17.760 ;
      RECT 0.048 18.432 46.882 18.528 ;
      RECT 0.048 19.200 46.882 19.296 ;
      RECT 0.048 19.968 46.882 20.064 ;
      RECT 0.048 20.736 46.882 20.832 ;
      RECT 0.048 21.504 46.882 21.600 ;
      RECT 0.048 22.272 46.882 22.368 ;
      RECT 0.048 23.040 46.882 23.136 ;
      RECT 0.048 23.808 46.882 23.904 ;
      RECT 0.048 24.576 46.882 24.672 ;
      RECT 0.048 25.344 46.882 25.440 ;
      RECT 0.048 26.112 46.882 26.208 ;
      RECT 0.048 26.880 46.882 26.976 ;
      RECT 0.048 27.648 46.882 27.744 ;
      RECT 0.048 28.416 46.882 28.512 ;
      RECT 0.048 29.184 46.882 29.280 ;
      RECT 0.048 29.952 46.882 30.048 ;
      RECT 0.048 30.720 46.882 30.816 ;
      RECT 0.048 31.488 46.882 31.584 ;
      RECT 0.048 32.256 46.882 32.352 ;
      RECT 0.048 33.024 46.882 33.120 ;
      RECT 0.048 33.792 46.882 33.888 ;
      RECT 0.048 34.560 46.882 34.656 ;
      RECT 0.048 35.328 46.882 35.424 ;
      RECT 0.048 36.096 46.882 36.192 ;
      RECT 0.048 36.864 46.882 36.960 ;
      RECT 0.048 37.632 46.882 37.728 ;
      RECT 0.048 38.400 46.882 38.496 ;
      RECT 0.048 39.168 46.882 39.264 ;
      RECT 0.048 39.936 46.882 40.032 ;
      RECT 0.048 40.704 46.882 40.800 ;
      RECT 0.048 41.472 46.882 41.568 ;
      RECT 0.048 42.240 46.882 42.336 ;
      RECT 0.048 43.008 46.882 43.104 ;
      RECT 0.048 43.776 46.882 43.872 ;
      RECT 0.048 44.544 46.882 44.640 ;
      RECT 0.048 45.312 46.882 45.408 ;
      RECT 0.048 46.080 46.882 46.176 ;
      RECT 0.048 46.848 46.882 46.944 ;
      RECT 0.048 47.616 46.882 47.712 ;
      RECT 0.048 48.384 46.882 48.480 ;
      RECT 0.048 49.152 46.882 49.248 ;
      RECT 0.048 49.920 46.882 50.016 ;
      RECT 0.048 50.688 46.882 50.784 ;
      RECT 0.048 51.456 46.882 51.552 ;
      RECT 0.048 52.224 46.882 52.320 ;
      RECT 0.048 52.992 46.882 53.088 ;
      RECT 0.048 53.760 46.882 53.856 ;
      RECT 0.048 54.528 46.882 54.624 ;
      RECT 0.048 55.296 46.882 55.392 ;
      RECT 0.048 56.064 46.882 56.160 ;
      RECT 0.048 56.832 46.882 56.928 ;
      RECT 0.048 57.600 46.882 57.696 ;
      RECT 0.048 58.368 46.882 58.464 ;
      RECT 0.048 59.136 46.882 59.232 ;
      RECT 0.048 59.904 46.882 60.000 ;
      RECT 0.048 60.672 46.882 60.768 ;
      RECT 0.048 61.440 46.882 61.536 ;
      RECT 0.048 62.208 46.882 62.304 ;
      RECT 0.048 62.976 46.882 63.072 ;
      RECT 0.048 63.744 46.882 63.840 ;
      RECT 0.048 64.512 46.882 64.608 ;
      RECT 0.048 65.280 46.882 65.376 ;
      RECT 0.048 66.048 46.882 66.144 ;
      RECT 0.048 66.816 46.882 66.912 ;
      RECT 0.048 67.584 46.882 67.680 ;
      RECT 0.048 68.352 46.882 68.448 ;
      RECT 0.048 69.120 46.882 69.216 ;
      RECT 0.048 69.888 46.882 69.984 ;
      RECT 0.048 70.656 46.882 70.752 ;
      RECT 0.048 71.424 46.882 71.520 ;
      RECT 0.048 72.192 46.882 72.288 ;
      RECT 0.048 72.960 46.882 73.056 ;
      RECT 0.048 73.728 46.882 73.824 ;
      RECT 0.048 74.496 46.882 74.592 ;
      RECT 0.048 75.264 46.882 75.360 ;
      RECT 0.048 76.032 46.882 76.128 ;
      RECT 0.048 76.800 46.882 76.896 ;
      RECT 0.048 77.568 46.882 77.664 ;
      RECT 0.048 78.336 46.882 78.432 ;
      RECT 0.048 79.104 46.882 79.200 ;
      RECT 0.048 79.872 46.882 79.968 ;
      RECT 0.048 80.640 46.882 80.736 ;
      RECT 0.048 81.408 46.882 81.504 ;
      RECT 0.048 82.176 46.882 82.272 ;
      RECT 0.048 82.944 46.882 83.040 ;
      RECT 0.048 83.712 46.882 83.808 ;
    END
  END VSS
  PIN VDD
    DIRECTION INOUT ;
    USE POWER ;
    PORT
      LAYER M4 ;
      RECT 0.048 0.384 46.882 0.480 ;
      RECT 0.048 1.152 46.882 1.248 ;
      RECT 0.048 1.920 46.882 2.016 ;
      RECT 0.048 2.688 46.882 2.784 ;
      RECT 0.048 3.456 46.882 3.552 ;
      RECT 0.048 4.224 46.882 4.320 ;
      RECT 0.048 4.992 46.882 5.088 ;
      RECT 0.048 5.760 46.882 5.856 ;
      RECT 0.048 6.528 46.882 6.624 ;
      RECT 0.048 7.296 46.882 7.392 ;
      RECT 0.048 8.064 46.882 8.160 ;
      RECT 0.048 8.832 46.882 8.928 ;
      RECT 0.048 9.600 46.882 9.696 ;
      RECT 0.048 10.368 46.882 10.464 ;
      RECT 0.048 11.136 46.882 11.232 ;
      RECT 0.048 11.904 46.882 12.000 ;
      RECT 0.048 12.672 46.882 12.768 ;
      RECT 0.048 13.440 46.882 13.536 ;
      RECT 0.048 14.208 46.882 14.304 ;
      RECT 0.048 14.976 46.882 15.072 ;
      RECT 0.048 15.744 46.882 15.840 ;
      RECT 0.048 16.512 46.882 16.608 ;
      RECT 0.048 17.280 46.882 17.376 ;
      RECT 0.048 18.048 46.882 18.144 ;
      RECT 0.048 18.816 46.882 18.912 ;
      RECT 0.048 19.584 46.882 19.680 ;
      RECT 0.048 20.352 46.882 20.448 ;
      RECT 0.048 21.120 46.882 21.216 ;
      RECT 0.048 21.888 46.882 21.984 ;
      RECT 0.048 22.656 46.882 22.752 ;
      RECT 0.048 23.424 46.882 23.520 ;
      RECT 0.048 24.192 46.882 24.288 ;
      RECT 0.048 24.960 46.882 25.056 ;
      RECT 0.048 25.728 46.882 25.824 ;
      RECT 0.048 26.496 46.882 26.592 ;
      RECT 0.048 27.264 46.882 27.360 ;
      RECT 0.048 28.032 46.882 28.128 ;
      RECT 0.048 28.800 46.882 28.896 ;
      RECT 0.048 29.568 46.882 29.664 ;
      RECT 0.048 30.336 46.882 30.432 ;
      RECT 0.048 31.104 46.882 31.200 ;
      RECT 0.048 31.872 46.882 31.968 ;
      RECT 0.048 32.640 46.882 32.736 ;
      RECT 0.048 33.408 46.882 33.504 ;
      RECT 0.048 34.176 46.882 34.272 ;
      RECT 0.048 34.944 46.882 35.040 ;
      RECT 0.048 35.712 46.882 35.808 ;
      RECT 0.048 36.480 46.882 36.576 ;
      RECT 0.048 37.248 46.882 37.344 ;
      RECT 0.048 38.016 46.882 38.112 ;
      RECT 0.048 38.784 46.882 38.880 ;
      RECT 0.048 39.552 46.882 39.648 ;
      RECT 0.048 40.320 46.882 40.416 ;
      RECT 0.048 41.088 46.882 41.184 ;
      RECT 0.048 41.856 46.882 41.952 ;
      RECT 0.048 42.624 46.882 42.720 ;
      RECT 0.048 43.392 46.882 43.488 ;
      RECT 0.048 44.160 46.882 44.256 ;
      RECT 0.048 44.928 46.882 45.024 ;
      RECT 0.048 45.696 46.882 45.792 ;
      RECT 0.048 46.464 46.882 46.560 ;
      RECT 0.048 47.232 46.882 47.328 ;
      RECT 0.048 48.000 46.882 48.096 ;
      RECT 0.048 48.768 46.882 48.864 ;
      RECT 0.048 49.536 46.882 49.632 ;
      RECT 0.048 50.304 46.882 50.400 ;
      RECT 0.048 51.072 46.882 51.168 ;
      RECT 0.048 51.840 46.882 51.936 ;
      RECT 0.048 52.608 46.882 52.704 ;
      RECT 0.048 53.376 46.882 53.472 ;
      RECT 0.048 54.144 46.882 54.240 ;
      RECT 0.048 54.912 46.882 55.008 ;
      RECT 0.048 55.680 46.882 55.776 ;
      RECT 0.048 56.448 46.882 56.544 ;
      RECT 0.048 57.216 46.882 57.312 ;
      RECT 0.048 57.984 46.882 58.080 ;
      RECT 0.048 58.752 46.882 58.848 ;
      RECT 0.048 59.520 46.882 59.616 ;
      RECT 0.048 60.288 46.882 60.384 ;
      RECT 0.048 61.056 46.882 61.152 ;
      RECT 0.048 61.824 46.882 61.920 ;
      RECT 0.048 62.592 46.882 62.688 ;
      RECT 0.048 63.360 46.882 63.456 ;
      RECT 0.048 64.128 46.882 64.224 ;
      RECT 0.048 64.896 46.882 64.992 ;
      RECT 0.048 65.664 46.882 65.760 ;
      RECT 0.048 66.432 46.882 66.528 ;
      RECT 0.048 67.200 46.882 67.296 ;
      RECT 0.048 67.968 46.882 68.064 ;
      RECT 0.048 68.736 46.882 68.832 ;
      RECT 0.048 69.504 46.882 69.600 ;
      RECT 0.048 70.272 46.882 70.368 ;
      RECT 0.048 71.040 46.882 71.136 ;
      RECT 0.048 71.808 46.882 71.904 ;
      RECT 0.048 72.576 46.882 72.672 ;
      RECT 0.048 73.344 46.882 73.440 ;
      RECT 0.048 74.112 46.882 74.208 ;
      RECT 0.048 74.880 46.882 74.976 ;
      RECT 0.048 75.648 46.882 75.744 ;
      RECT 0.048 76.416 46.882 76.512 ;
      RECT 0.048 77.184 46.882 77.280 ;
      RECT 0.048 77.952 46.882 78.048 ;
      RECT 0.048 78.720 46.882 78.816 ;
      RECT 0.048 79.488 46.882 79.584 ;
      RECT 0.048 80.256 46.882 80.352 ;
      RECT 0.048 81.024 46.882 81.120 ;
      RECT 0.048 81.792 46.882 81.888 ;
      RECT 0.048 82.560 46.882 82.656 ;
      RECT 0.048 83.328 46.882 83.424 ;
    END
  END VDD
  OBS
    LAYER M1 ;
    RECT 0 0 46.930 84.000 ;
    LAYER M2 ;
    RECT 0 0 46.930 84.000 ;
    LAYER M3 ;
    RECT 0 0 46.930 84.000 ;
    LAYER M4 ;
    RECT 0 0 46.930 84.000 ;
  END
END fakeram7_dp_2048x32

END LIBRARY
